VERSION 5.4 ;
NAMESCASESENSITIVE ON ;
BUSBITCHARS "[]" ;
DIVIDERCHAR "/" ;
UNITS
  DATABASE MICRONS 2000 ;
END UNITS
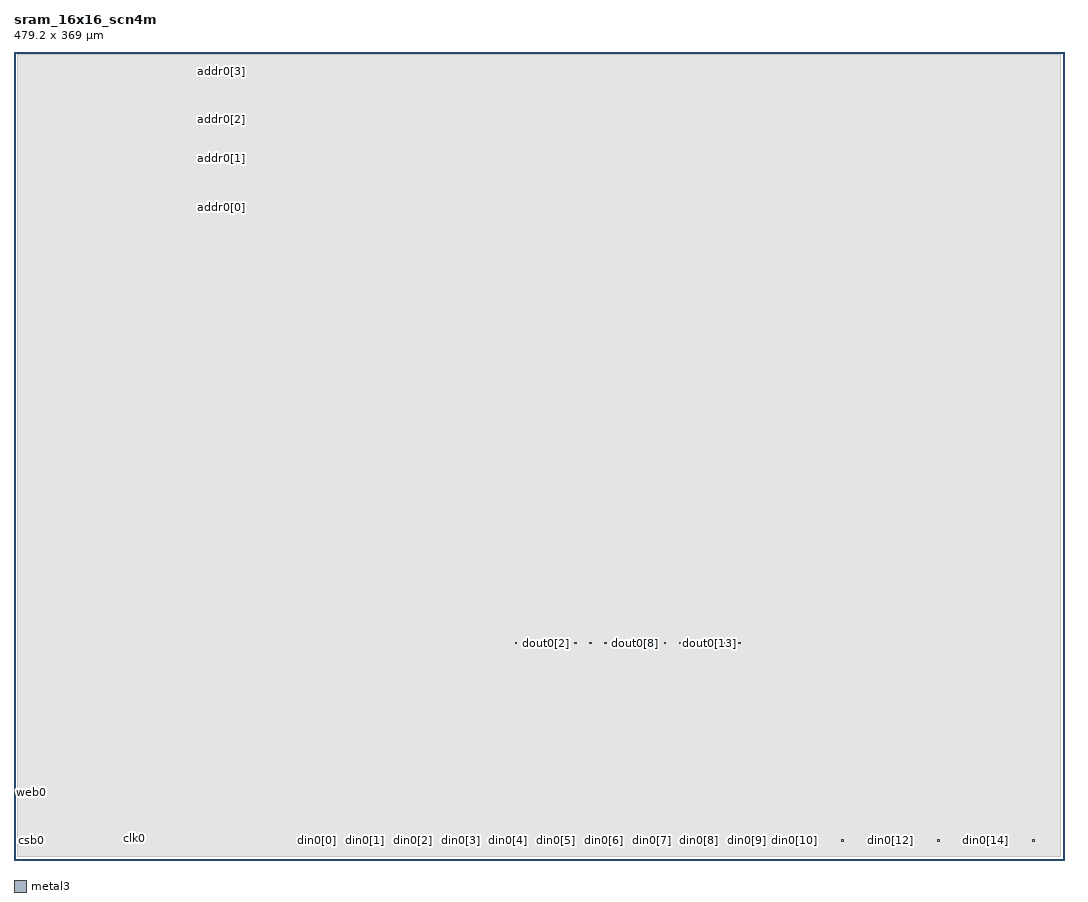
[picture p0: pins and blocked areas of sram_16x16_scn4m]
MACRO sram_16x16_scn4m
   CLASS BLOCK ;
   SIZE 479.2 BY 369.0 ;
   SYMMETRY X Y R90 ;
   PIN din0[0]
      DIRECTION INPUT ;
      PORT
         LAYER metal3 ;
         RECT  138.0 8.6 138.8 9.4 ;
      END
   END din0[0]
   PIN din0[1]
      DIRECTION INPUT ;
      PORT
         LAYER metal3 ;
         RECT  159.8 8.6 160.6 9.4 ;
      END
   END din0[1]
   PIN din0[2]
      DIRECTION INPUT ;
      PORT
         LAYER metal3 ;
         RECT  181.6 8.6 182.4 9.4 ;
      END
   END din0[2]
   PIN din0[3]
      DIRECTION INPUT ;
      PORT
         LAYER metal3 ;
         RECT  203.4 8.6 204.2 9.4 ;
      END
   END din0[3]
   PIN din0[4]
      DIRECTION INPUT ;
      PORT
         LAYER metal3 ;
         RECT  225.2 8.6 226.0 9.4 ;
      END
   END din0[4]
   PIN din0[5]
      DIRECTION INPUT ;
      PORT
         LAYER metal3 ;
         RECT  247.0 8.6 247.8 9.4 ;
      END
   END din0[5]
   PIN din0[6]
      DIRECTION INPUT ;
      PORT
         LAYER metal3 ;
         RECT  268.8 8.6 269.6 9.4 ;
      END
   END din0[6]
   PIN din0[7]
      DIRECTION INPUT ;
      PORT
         LAYER metal3 ;
         RECT  290.6 8.6 291.4 9.4 ;
      END
   END din0[7]
   PIN din0[8]
      DIRECTION INPUT ;
      PORT
         LAYER metal3 ;
         RECT  312.4 8.6 313.2 9.4 ;
      END
   END din0[8]
   PIN din0[9]
      DIRECTION INPUT ;
      PORT
         LAYER metal3 ;
         RECT  334.2 8.6 335.0 9.4 ;
      END
   END din0[9]
   PIN din0[10]
      DIRECTION INPUT ;
      PORT
         LAYER metal3 ;
         RECT  356.0 8.6 356.8 9.4 ;
      END
   END din0[10]
   PIN din0[11]
      DIRECTION INPUT ;
      PORT
         LAYER metal3 ;
         RECT  377.8 8.6 378.6 9.4 ;
      END
   END din0[11]
   PIN din0[12]
      DIRECTION INPUT ;
      PORT
         LAYER metal3 ;
         RECT  399.6 8.6 400.4 9.4 ;
      END
   END din0[12]
   PIN din0[13]
      DIRECTION INPUT ;
      PORT
         LAYER metal3 ;
         RECT  421.4 8.6 422.2 9.4 ;
      END
   END din0[13]
   PIN din0[14]
      DIRECTION INPUT ;
      PORT
         LAYER metal3 ;
         RECT  443.2 8.6 444.0 9.4 ;
      END
   END din0[14]
   PIN din0[15]
      DIRECTION INPUT ;
      PORT
         LAYER metal3 ;
         RECT  465.0 8.6 465.8 9.4 ;
      END
   END din0[15]
   PIN addr0[0]
      DIRECTION INPUT ;
      PORT
         LAYER metal3 ;
         RECT  94.4 297.6 95.2 298.4 ;
      END
   END addr0[0]
   PIN addr0[1]
      DIRECTION INPUT ;
      PORT
         LAYER metal3 ;
         RECT  94.4 319.6 95.2 320.4 ;
      END
   END addr0[1]
   PIN addr0[2]
      DIRECTION INPUT ;
      PORT
         LAYER metal3 ;
         RECT  94.4 337.6 95.2 338.4 ;
      END
   END addr0[2]
   PIN addr0[3]
      DIRECTION INPUT ;
      PORT
         LAYER metal3 ;
         RECT  94.4 359.6 95.2 360.4 ;
      END
   END addr0[3]
   PIN csb0
      DIRECTION INPUT ;
      PORT
         LAYER metal3 ;
         RECT  7.6 8.6 8.4 9.4 ;
      END
   END csb0
   PIN web0
      DIRECTION INPUT ;
      PORT
         LAYER metal3 ;
         RECT  7.6 30.6 8.4 31.4 ;
      END
   END web0
   PIN clk0
      DIRECTION INPUT ;
      PORT
         LAYER metal3 ;
         RECT  54.8 9.4 55.6 10.2 ;
      END
   END clk0
   PIN dout0[0]
      DIRECTION OUTPUT ;
      PORT
         LAYER metal3 ;
         RECT  228.7 98.6 229.5 99.4 ;
      END
   END dout0[0]
   PIN dout0[1]
      DIRECTION OUTPUT ;
      PORT
         LAYER metal3 ;
         RECT  235.5 98.6 236.3 99.4 ;
      END
   END dout0[1]
   PIN dout0[2]
      DIRECTION OUTPUT ;
      PORT
         LAYER metal3 ;
         RECT  242.3 98.6 243.1 99.4 ;
      END
   END dout0[2]
   PIN dout0[3]
      DIRECTION OUTPUT ;
      PORT
         LAYER metal3 ;
         RECT  249.1 98.6 249.9 99.4 ;
      END
   END dout0[3]
   PIN dout0[4]
      DIRECTION OUTPUT ;
      PORT
         LAYER metal3 ;
         RECT  255.9 98.6 256.7 99.4 ;
      END
   END dout0[4]
   PIN dout0[5]
      DIRECTION OUTPUT ;
      PORT
         LAYER metal3 ;
         RECT  262.7 98.6 263.5 99.4 ;
      END
   END dout0[5]
   PIN dout0[6]
      DIRECTION OUTPUT ;
      PORT
         LAYER metal3 ;
         RECT  269.5 98.6 270.3 99.4 ;
      END
   END dout0[6]
   PIN dout0[7]
      DIRECTION OUTPUT ;
      PORT
         LAYER metal3 ;
         RECT  276.3 98.6 277.1 99.4 ;
      END
   END dout0[7]
   PIN dout0[8]
      DIRECTION OUTPUT ;
      PORT
         LAYER metal3 ;
         RECT  283.1 98.6 283.9 99.4 ;
      END
   END dout0[8]
   PIN dout0[9]
      DIRECTION OUTPUT ;
      PORT
         LAYER metal3 ;
         RECT  289.9 98.6 290.7 99.4 ;
      END
   END dout0[9]
   PIN dout0[10]
      DIRECTION OUTPUT ;
      PORT
         LAYER metal3 ;
         RECT  296.7 98.6 297.5 99.4 ;
      END
   END dout0[10]
   PIN dout0[11]
      DIRECTION OUTPUT ;
      PORT
         LAYER metal3 ;
         RECT  303.5 98.6 304.3 99.4 ;
      END
   END dout0[11]
   PIN dout0[12]
      DIRECTION OUTPUT ;
      PORT
         LAYER metal3 ;
         RECT  310.3 98.6 311.1 99.4 ;
      END
   END dout0[12]
   PIN dout0[13]
      DIRECTION OUTPUT ;
      PORT
         LAYER metal3 ;
         RECT  317.1 98.6 317.9 99.4 ;
      END
   END dout0[13]
   PIN dout0[14]
      DIRECTION OUTPUT ;
      PORT
         LAYER metal3 ;
         RECT  323.9 98.6 324.7 99.4 ;
      END
   END dout0[14]
   PIN dout0[15]
      DIRECTION OUTPUT ;
      PORT
         LAYER metal3 ;
         RECT  330.7 98.6 331.5 99.4 ;
      END
   END dout0[15]
   PIN vdd
      DIRECTION INOUT ;
      USE POWER ; 
      SHAPE ABUTMENT ; 
      PORT
      END
   END vdd
   PIN gnd
      DIRECTION INOUT ;
      USE GROUND ; 
      SHAPE ABUTMENT ; 
      PORT
      END
   END gnd
   OBS
   LAYER  metal1 ;
      RECT  1.4 1.4 477.8 367.6 ;
   LAYER  metal2 ;
      RECT  1.4 1.4 477.8 367.6 ;
   LAYER  metal3 ;
      RECT  1.4 1.4 136.8 7.4 ;
      RECT  136.8 1.4 140.0 7.4 ;
      RECT  136.8 10.6 140.0 367.6 ;
      RECT  140.0 1.4 477.8 7.4 ;
      RECT  140.0 7.4 158.6 10.6 ;
      RECT  161.8 7.4 180.4 10.6 ;
      RECT  183.6 7.4 202.2 10.6 ;
      RECT  205.4 7.4 224.0 10.6 ;
      RECT  227.2 7.4 245.8 10.6 ;
      RECT  249.0 7.4 267.6 10.6 ;
      RECT  270.8 7.4 289.4 10.6 ;
      RECT  292.6 7.4 311.2 10.6 ;
      RECT  314.4 7.4 333.0 10.6 ;
      RECT  336.2 7.4 354.8 10.6 ;
      RECT  358.0 7.4 376.6 10.6 ;
      RECT  379.8 7.4 398.4 10.6 ;
      RECT  401.6 7.4 420.2 10.6 ;
      RECT  423.4 7.4 442.0 10.6 ;
      RECT  445.2 7.4 463.8 10.6 ;
      RECT  467.0 7.4 477.8 10.6 ;
      RECT  1.4 296.4 93.2 299.6 ;
      RECT  1.4 299.6 93.2 367.6 ;
      RECT  93.2 10.6 96.4 296.4 ;
      RECT  96.4 10.6 136.8 296.4 ;
      RECT  96.4 296.4 136.8 299.6 ;
      RECT  96.4 299.6 136.8 367.6 ;
      RECT  93.2 299.6 96.4 318.4 ;
      RECT  93.2 321.6 96.4 336.4 ;
      RECT  93.2 339.6 96.4 358.4 ;
      RECT  93.2 361.6 96.4 367.6 ;
      RECT  1.4 7.4 6.4 10.6 ;
      RECT  1.4 10.6 6.4 29.4 ;
      RECT  1.4 29.4 6.4 32.6 ;
      RECT  1.4 32.6 6.4 296.4 ;
      RECT  6.4 10.6 9.6 29.4 ;
      RECT  6.4 32.6 9.6 296.4 ;
      RECT  9.6 29.4 93.2 32.6 ;
      RECT  9.6 32.6 93.2 296.4 ;
      RECT  9.6 7.4 53.6 8.2 ;
      RECT  9.6 8.2 53.6 10.6 ;
      RECT  53.6 7.4 56.8 8.2 ;
      RECT  56.8 7.4 136.8 8.2 ;
      RECT  56.8 8.2 136.8 10.6 ;
      RECT  9.6 10.6 53.6 11.4 ;
      RECT  9.6 11.4 53.6 29.4 ;
      RECT  53.6 11.4 56.8 29.4 ;
      RECT  56.8 10.6 93.2 11.4 ;
      RECT  56.8 11.4 93.2 29.4 ;
      RECT  140.0 10.6 227.5 97.4 ;
      RECT  140.0 97.4 227.5 100.6 ;
      RECT  140.0 100.6 227.5 367.6 ;
      RECT  227.5 10.6 230.7 97.4 ;
      RECT  227.5 100.6 230.7 367.6 ;
      RECT  230.7 10.6 477.8 97.4 ;
      RECT  230.7 100.6 477.8 367.6 ;
      RECT  230.7 97.4 234.3 100.6 ;
      RECT  237.5 97.4 241.1 100.6 ;
      RECT  244.3 97.4 247.9 100.6 ;
      RECT  251.1 97.4 254.7 100.6 ;
      RECT  257.9 97.4 261.5 100.6 ;
      RECT  264.7 97.4 268.3 100.6 ;
      RECT  271.5 97.4 275.1 100.6 ;
      RECT  278.3 97.4 281.9 100.6 ;
      RECT  285.1 97.4 288.7 100.6 ;
      RECT  291.9 97.4 295.5 100.6 ;
      RECT  298.7 97.4 302.3 100.6 ;
      RECT  305.5 97.4 309.1 100.6 ;
      RECT  312.3 97.4 315.9 100.6 ;
      RECT  319.1 97.4 322.7 100.6 ;
      RECT  325.9 97.4 329.5 100.6 ;
      RECT  332.7 97.4 477.8 100.6 ;
   LAYER  metal4 ;
      RECT  1.4 1.4 477.8 367.6 ;
   END
END    sram_16x16_scn4m
END    LIBRARY
